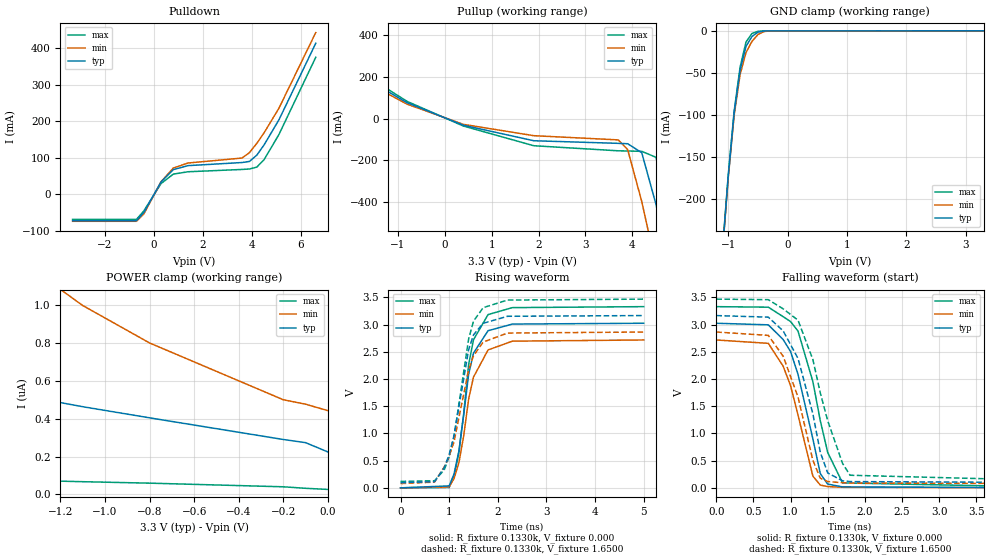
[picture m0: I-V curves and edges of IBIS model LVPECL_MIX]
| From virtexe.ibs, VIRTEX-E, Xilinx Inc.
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|   Model LVPECL_MIX
[Model]   LVPECL_MIX
Model_type   I/O
Polarity   Non-Inverting
Enable   Active-Low
Vinh  = 1.49V
Vinl  = 0.86V
Vmeas =   1.6500V
Cref =  10.0000pF
Rref =   1.0000M
Vref =  0.000V
C_comp   5.0000pF   4.0000pF   6.0000pF
[Temperature Range]   85.0000   85.0000   85.0000
[Voltage Range]   3.3000V   3.0000V   3.6000V
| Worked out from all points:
|   slope of the pulldown table from 0 to 0.495 V, typ, clamps not added: 9.94 ohm
|   slope of the pullup table from 0 to 0.495 V, typ, clamps not added: 12.6 ohm
|   GND clamp passes 1 mA (typ) near -0.45 V on its own axis
|   rising waveform, R_fixture 0.1330k, V_fixture 0.000: 20-80 % time 302ps typ, 352ps min, 285ps max; typ from 0 V to 3.02 V
|   rising waveform, R_fixture 0.1330k, V_fixture 1.6500: 20-80 % time 378ps typ, 434ps min, 360ps max; typ from 0.096 V to 3.16 V
|   falling waveform, R_fixture 0.1330k, V_fixture 0.000: 20-80 % time 326ps typ, 316ps min, 341ps max; typ from 3.02 V to 0 V
|   falling waveform, R_fixture 0.1330k, V_fixture 1.6500: 20-80 % time 345ps typ, 340ps min, 419ps max; typ from 3.16 V to 0.096 V
[Pulldown]
| voltage   I(typ)   I(min)   I(max)
-3.3V     -72.38mA   -74.24mA   -68.88mA
-700mV    -72.38mA   -74.24mA   -68.88mA
-400mV    -50.35mA   -54.31mA   -45.82mA
300mV     33.38mA    34mA       28.98mA
800mV     67.26mA    71.6mA     54.94mA
1.4V      78.19mA    85.32mA    61.41mA
3.6V      86.67mA    98.96mA    67.72mA
3.9V      89.65mA    113.9mA    68.97mA
4.2V      106.9mA    139.2mA    74.11mA
4.5V      135.4mA    168.5mA    94.89mA
5.1V      203.5mA    235.3mA    163.3mA
6.6V      413.2mA    442.5mA    374.8mA
[Pullup]
| voltage   I(typ)   I(min)   I(max)
-3.3V     404.8mA    370.8mA    438.4mA
-800mV    75.94mA    69.07mA    82.51mA
400mV     -32.24mA   -28.07mA   -36.21mA
1.9V      -106.9mA   -82.55mA   -130.9mA
3.7V      -119.4mA   -102.8mA   -155.3mA
3.9V      -121.3mA   -149.6mA   -156.2mA
4.2V      -164.4mA   -399.4mA   -157.9mA
4.5V      -410.3mA   -706.6mA   -186.2mA
4.7V      -612.9mA   -918.1mA   -329.2mA
4.9V      -822.4mA   -1.132A    -523.6mA
5.1V      -1.035A    -1.347A    -729.9mA
6.6V      -2.667A    -2.986A    -2.351A
[GND_clamp]
| voltage   I(typ)   I(min)   I(max)
-3.3V     -2.624A    -2.624A    -2.624A
-1.1V     -265.9mA   -267.2mA   -264.8mA
-1V       -174.1mA   -176mA     -172.7mA
-900mV    -98.16mA   -101.1mA   -96.02mA
-800mV    -47.1mA    -52.22mA   -43.45mA
-700mV    -18.56mA   -25.86mA   -13.29mA
-600mV    -6.79mA    -12.65mA   -3.223mA
-500mV    -1.656mA   -4.488mA   -548.6uA
-400mV    -239.4uA   -899.1uA   -68.47uA
-300mV    -25.58uA   -114.5uA   -6.532uA
3.3V      71.77nA    1.445uA    12.46nA
[POWER_clamp]
| voltage   I(typ)   I(min)   I(max)
-3.3V     1.385uA    7.507uA    174.7nA
-3.1V     1.234uA    6.162uA    158.6nA
-2.6V     941.1nA    3.772uA    125.8nA
-2.3V     808.2nA    2.826uA    110.5nA
-1.9V     666.3nA    1.95uA     93.13nA
-1.4V     530.2nA    1.266uA    75.61nA
-1.3V     506.9nA    1.168uA    72.64nA
-1.1V     463.3nA    998.2nA    66.94nA
-800mV    404.5nA    800.2nA    59.2nA
-200mV    290nA      500nA      40nA
-100mV    273.2nA    476.7nA    32nA
0V        224.2nA    442.3nA    26.08nA
[Ramp]
| variable   typ   min   max
dV/dt_r   1.8138/0.3199n   1.6296/0.3523n   1.9968/0.3075n
dV/dt_f   1.8599/0.4017n   1.7029/0.3574n   2.0076/0.5037n
R_load = 0.1330k
[Rising Waveform]
R_fixture = 0.1330k
V_fixture = 0.000
| time   V(typ)   V(min)   V(max)
0s        1.651uV    0V         2.118uV
1ns       36.04mV    17.86mV    6.385mV
1.1ns     253.3mV    168.9mV    213.4mV
1.2ns     673.5mV    460mV      648.9mV
1.3ns     1.345V     961.7mV    1.374V
1.4ns     2.081V     1.627V     2.26V
1.5ns     2.474V     2.033V     2.719V
1.8ns     2.886V     2.533V     3.182V
2.3ns     3.008V     2.694V     3.31V
5ns       3.023V     2.716V     3.328V
[Rising Waveform]
R_fixture = 0.1330k
V_fixture = 1.6500
V_fixture_min = 1.5000
V_fixture_max = 1.8000
| time   V(typ)   V(min)   V(max)
0s        95.65mV    78.43mV    118.5mV
700ps     113.8mV    105.8mV    130.8mV
900ps     370.7mV    385.2mV    332.1mV
1ns       609.6mV    580.1mV    569.6mV
1.1ns     961.6mV    846.4mV    937.7mV
1.4ns     2.534V     2.165V     2.732V
1.5ns     2.808V     2.424V     3.061V
1.7ns     3.022V     2.678V     3.309V
2.2ns     3.151V     2.843V     3.449V
5ns       3.164V     2.862V     3.466V
[Falling Waveform]
R_fixture = 0.1330k
V_fixture = 0.000
| time   V(typ)   V(min)   V(max)
0s        3.023V     2.716V     3.328V
700ps     2.994V     2.654V     3.318V
900ps     2.724V     2.235V     3.144V
1ns       2.503V     1.876V     3.054V
1.1ns     2.086V     1.336V     2.879V
1.3ns     900mV      216mV      1.951V
1.4ns     262.3mV    51.08mV    1.233V
1.5ns     69.3mV     23.51mV    648.5mV
1.7ns     17.74mV    10.91mV    91mV
5ns       197.8uV    217.1uV    265.1uV
[Falling Waveform]
R_fixture = 0.1330k
V_fixture = 1.6500
V_fixture_min = 1.5000
V_fixture_max = 1.8000
| time   V(typ)   V(min)   V(max)
0s        3.164V     2.862V     3.466V
700ps     3.135V     2.8V       3.456V
900ps     2.883V     2.418V     3.288V
1.1ns     2.377V     1.668V     3.079V
1.3ns     1.361V     506.1mV    2.357V
1.4ns     653.3mV    176.6mV    1.744V
1.5ns     273mV      116.2mV    1.232V
1.7ns     130.2mV    93.94mV    448.4mV
1.8ns     115.3mV    89.17mV    231.9mV
5ns       95.86mV    78.71mV    118.7mV
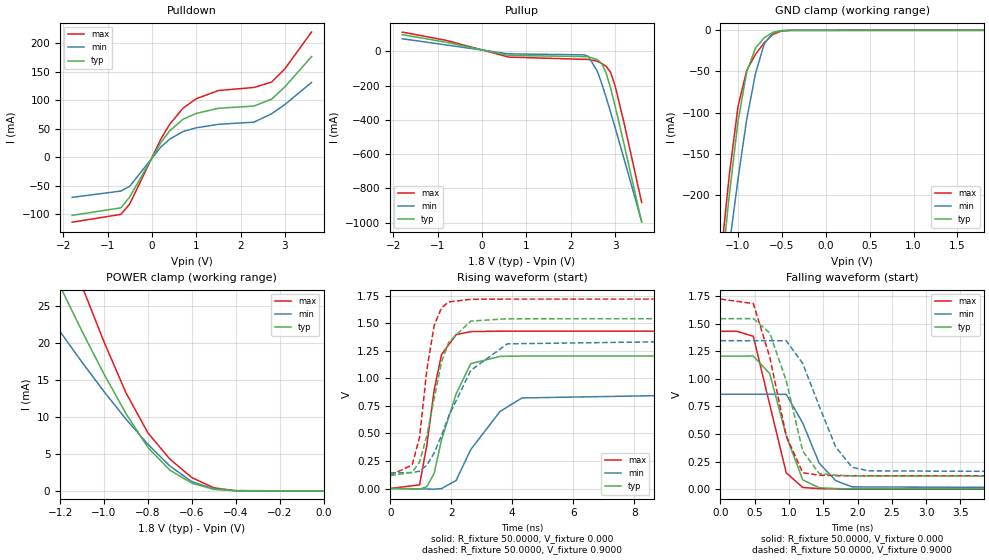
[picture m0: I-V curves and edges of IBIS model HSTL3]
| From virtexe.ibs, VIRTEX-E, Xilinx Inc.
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|   Model HSTL3
[Model]   HSTL3
Model_type   I/O
Polarity   Non-Inverting
Enable   Active-Low
Vmeas =   0.9000V
Vinl =  0.8000V
Vinh =  1.0000V
Cref =  20.0000pF
Rref =  50.0000
Vref =   0.9000V
C_comp   6.0000pF   5.0000pF   7.0000pF
[Temperature Range]   25.0000   100.0000   0.000
[Voltage Range]   1.8000V   1.7000V   1.9000V
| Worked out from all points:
|   slope of the pulldown table from 0 to 0.27 V, typ, clamps not added: 8.08 ohm
|   slope of the pullup table from 0 to 0.27 V, typ, clamps not added: 20.1 ohm
|   GND clamp passes 1 mA (typ) near -0.54 V on its own axis
|   POWER clamp passes 1 mA (typ) near -0.59 V on its own axis
|   rising waveform, R_fixture 50.0000, V_fixture 0.000: 20-80 % time 777ps typ, 1.23ns min, 498ps max; typ from 0 V to 1.21 V
|   rising waveform, R_fixture 50.0000, V_fixture 0.9000: 20-80 % time 702ps typ, 1.21ns min, 457ps max; typ from 0.116 V to 1.54 V
|   falling waveform, R_fixture 50.0000, V_fixture 0.000: 20-80 % time 351ps typ, 419ps min, 333ps max; typ from 1.21 V to 0 V
|   falling waveform, R_fixture 50.0000, V_fixture 0.9000: 20-80 % time 372ps typ, 459ps min, 372ps max; typ from 1.54 V to 0.116 V
[Pulldown]
| voltage   I(typ)   I(min)   I(max)
-1.8V     -101.8mA   -70.26mA   -113.8mA
-700mV    -88.66mA   -59.16mA   -100.1mA
-500mV    -69.51mA   -50.85mA   -81.74mA
200mV     25.8mA     17.93mA    31.7mA
400mV     46.21mA    31.81mA    57.78mA
700mV     66.68mA    45.16mA    86.08mA
1V        76.94mA    51.73mA    102.7mA
1.5V      85.98mA    57.82mA    117.1mA
2.3V      89.85mA    61.65mA    122.5mA
2.7V      102mA      76.37mA    131.9mA
3V        123.6mA    92.61mA    155.3mA
3.6V      176.6mA    131.3mA    219.6mA
[Pullup]
| voltage   I(typ)   I(min)   I(max)
-1.8V     97.04mA    72.78mA    111.7mA
-800mV    51.88mA    36.3mA     62.98mA
600mV     -24.24mA   -15.32mA   -34.04mA
2.3V      -31.3mA    -20.95mA   -47.36mA
2.4V      -32.73mA   -30.87mA   -47.8mA
2.6V      -49.01mA   -116.6mA   -58.63mA
2.7V      -71.91mA   -188.9mA   -71.8mA
2.8V      -127.2mA   -270.6mA   -88.68mA
2.9V      -216mA     -356.6mA   -122.6mA
3V        -319mA     -444.8mA   -201.1mA
3.2V      -539.1mA   -625.1mA   -414.5mA
3.6V      -997.5mA   -993.6mA   -882.6mA
[GND_clamp]
| voltage   I(typ)   I(min)   I(max)
-1.8V     -984.2mA   -893.8mA   -981.3mA
-1.2V     -305.4mA   -349.4mA   -281.7mA
-1.1V     -201.6mA   -263.3mA   -177.2mA
-1V       -111.1mA   -181.2mA   -92.91mA
-900mV    -50.62mA   -108.2mA   -48.68mA
-800mV    -21.39mA   -52.51mA   -29.19mA
-700mV    -9.057mA   -16.26mA   -15mA
-600mV    -2.332mA   -3.044mA   -4.887mA
-500mV    -280.5uA   -493uA     -684.1uA
-400mV    -21.31uA   -72.94uA   -46.93uA
1.8V      9.75nA     24.68nA    9.371nA
[POWER_clamp]
| voltage   I(typ)   I(min)   I(max)
-1.8V     67.36mA    47.92mA    87.19mA
-1.3V     33.96mA    25.81mA    43.76mA
-1.2V     27.64mA    21.52mA    35.56mA
-1.1V     21.56mA    17.38mA    27.65mA
-1V       15.79mA    13.42mA    20.13mA
-900mV    10.45mA    9.702mA    13.26mA
-800mV    5.872mA    6.297mA    7.84mA
-700mV    2.804mA    3.371mA    4.298mA
-600mV    1.052mA    1.252mA    1.806mA
-500mV    210uA      278.7uA    420.1uA
-400mV    17.08uA    35.57uA    36.55uA
0V        9.75nA     16.07nA    10.24nA
[Ramp]
| variable   typ   min   max
dV/dt_r   0.7230/0.7358n   0.5157/1.2099n   0.8580/0.4715n
dV/dt_f   0.9319/0.3893n   0.8220/0.5882n   1.0115/0.3214n
R_load = 50.0000
[Rising Waveform]
R_fixture = 50.0000
V_fixture = 0.000
| time   V(typ)   V(min)   V(max)
0s        -41.76uV   -22.54uV   -60.93uV
960ps     -5.628mV   -2.364mV   33.39mV
1.2ns     16.2mV     -4.894mV   394.4mV
1.44ns    137.6mV    -6.008mV   894.9mV
1.68ns    441.5mV    -772.3uV   1.217V
2.16ns    859.5mV    73.07mV    1.399V
2.64ns    1.135V     354mV      1.426V
3.6ns     1.201V     700.1mV    1.43V
4.32ns    1.204V     823.2mV    1.43V
12ns      1.205V     859.5mV    1.43V
[Rising Waveform]
R_fixture = 50.0000
V_fixture = 0.9000
V_fixture_min = 0.8000
V_fixture_max = 1.1000
| time   V(typ)   V(min)   V(max)
0s        116.4mV    142.1mV    119.4mV
720ps     147.5mV    143.8mV    214.8mV
960ps     239.5mV    157.8mV    466.6mV
1.2ns     480.3mV    213.7mV    1.078V
1.44ns    818.7mV    322.8mV    1.482V
1.68ns    1.15V      481.4mV    1.642V
1.92ns    1.331V     658.7mV    1.696V
2.64ns    1.522V     1.073V     1.72V
3.84ns    1.543V     1.315V     1.722V
12ns      1.544V     1.345V     1.722V
[Falling Waveform]
R_fixture = 50.0000
V_fixture = 0.000
| time   V(typ)   V(min)   V(max)
0s        1.205V     859.6mV    1.43V
240ps     1.205V     859.6mV    1.43V
480ps     1.206V     859.6mV    1.385V
720ps     1.046V     859.9mV    764.1mV
960ps     482.6mV    858.9mV    148mV
1.2ns     84.3mV     599.6mV    15.72mV
1.44ns    13.28mV    236.2mV    4.709mV
1.68ns    5.358mV    77.77mV    2.238mV
1.92ns    2.688mV    20.56mV    1.234mV
12ns      55.62uV    99.74uV    40.95uV
[Falling Waveform]
R_fixture = 50.0000
V_fixture = 0.9000
V_fixture_min = 0.8000
V_fixture_max = 1.1000
| time   V(typ)   V(min)   V(max)
0s        1.544V     1.345V     1.722V
480ps     1.545V     1.345V     1.681V
720ps     1.415V     1.345V     1.197V
960ps     982.1mV    1.345V     482.6mV
1.2ns     345mV      1.139V     149.3mV
1.44ns    142.4mV    754mV      127mV
1.68ns    125.8mV    383.2mV    122.8mV
1.92ns    120.8mV    198.5mV    121.2mV
2.16ns    119mV      165.9mV    120.6mV
12ns      116.5mV    142.2mV    119.6mV
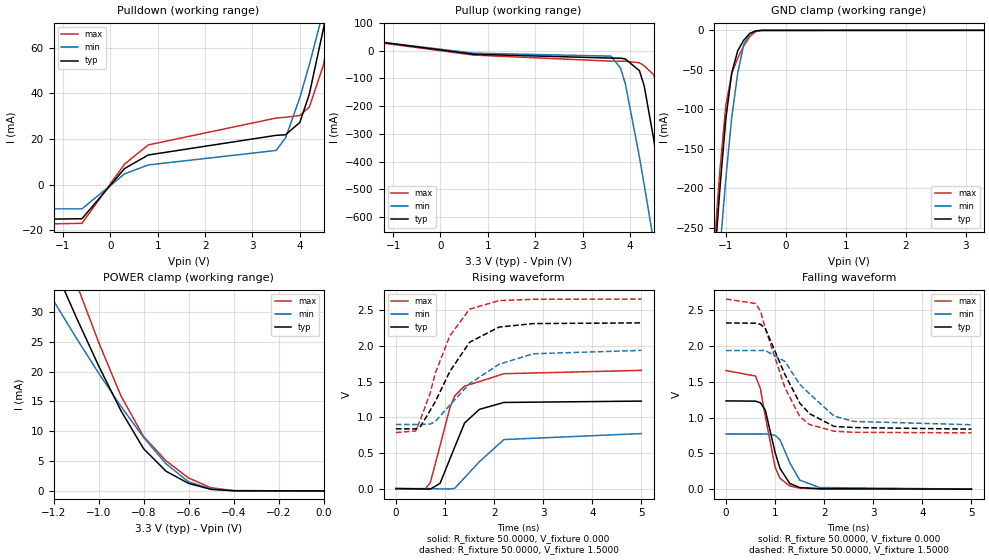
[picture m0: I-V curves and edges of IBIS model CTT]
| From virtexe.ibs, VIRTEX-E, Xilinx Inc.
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|   Model CTT
[Model]   CTT
Model_type   I/O
Polarity   Non-Inverting
Enable   Active-Low
Vinl =   1.300V
Vinh =   1.700V
Vmeas =   1.5000V
Cref =  20.0000pF
Rref =  50.0000
Vref =   1.5000V
C_comp   5.0000pF   4.0000pF   6.0000pF
[Temperature Range]   25.0000   100.0000   0.000
[Voltage Range]   3.3000V   3.0000V   3.6000V
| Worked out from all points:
|   slope of the pulldown table from 0 to 0.495 V, typ, clamps not added: 48.8 ohm
|   slope of the pullup table from 0 to 0.495 V, typ, clamps not added: 53.2 ohm
|   GND clamp passes 1 mA (typ) near -0.51 V on its own axis
|   POWER clamp passes 1 mA (typ) near -0.57 V on its own axis
|   rising waveform, R_fixture 50.0000, V_fixture 0.000: 20-80 % time 463ps typ, 641ps min, 427ps max; typ from 0 V to 1.23 V
|   rising waveform, R_fixture 50.0000, V_fixture 1.5000: 20-80 % time 737ps typ, 1.07ns min, 612ps max; typ from 0.838 V to 2.32 V
|   falling waveform, R_fixture 50.0000, V_fixture 0.000: 20-80 % time 288ps typ, 318ps min, 271ps max; typ from 1.23 V to 0.001 V
|   falling waveform, R_fixture 50.0000, V_fixture 1.5000: 20-80 % time 668ps typ, 798ps min, 589ps max; typ from 2.32 V to 0.839 V
[Pulldown]
| voltage   I(typ)   I(min)   I(max)
-3.3V     -15.5mA    -10.58mA   -17.86mA
-600mV    -14.92mA   -10.58mA   -16.93mA
300mV     7.091mA    4.772mA    9.036mA
800mV     13.02mA    8.645mA    17.43mA
3.5V      21.63mA    15.01mA    29.2mA
3.7V      21.89mA    20.56mA    29.55mA
4V        27.27mA    38.14mA    30.32mA
4.2V      39.63mA    52.54mA    34mA
4.5V      68.49mA    76.43mA    52.45mA
4.7V      90.09mA    93.42mA    75.12mA
4.9V      112.8mA    111.1mA    100.8mA
6.6V      325.4mA    277.2mA    349.4mA
[Pullup]
| voltage   I(typ)   I(min)   I(max)
-3.3V     76.5mA     72.6mA     74.8mA
700mV     -12.61mA   -8.706mA   -15.61mA
3.6V      -26.42mA   -19.4mA    -37.49mA
3.8V      -26.91mA   -62.44mA   -37.69mA
3.9V      -29.44mA   -116.9mA   -37.79mA
4.2V      -71.79mA   -383mA     -43.41mA
4.3V      -126.2mA   -482.7mA   -54.06mA
4.5V      -317.3mA   -687.1mA   -86.33mA
4.7V      -537mA     -895.1mA   -197.6mA
4.9V      -764.2mA   -1.105A    -410.4mA
5.1V      -994.9mA   -1.316A    -641.1mA
6.6V      -2.76A     -2.923A    -2.453A
[GND_clamp]
| voltage   I(typ)   I(min)   I(max)
-3.3V     -2.749A    -2.594A    -2.804A
-1.2V     -306mA     -377.1mA   -282.7mA
-1.1V     -202.5mA   -280mA     -178.8mA
-1V       -112.5mA   -188.5mA   -95.98mA
-900mV    -53.5mA    -109.7mA   -54.53mA
-800mV    -25.67mA   -53.59mA   -35.13mA
-700mV    -12.44mA   -17.88mA   -19.82mA
-600mV    -3.982mA   -4.202mA   -7.865mA
-500mV    -601.5uA   -800.3uA   -1.508mA
-400mV    -51.05uA   -119.3uA   -124.3uA
3.3V      18.74nA    3.634uA    18.92nA
[POWER_clamp]
| voltage   I(typ)   I(min)   I(max)
-3.3V     237mA      175.9mA    284.4mA
-1.3V     46.69mA    38.29mA    56.33mA
-1.2V     37.79mA    31.9mA     45.45mA
-1.1V     29.2mA     25.71mA    34.95mA
-1V       21.01mA    19.78mA    24.97mA
-900mV    13.43mA    14.17mA    15.91mA
-800mV    7.091mA    8.993mA    9.139mA
-700mV    3.305mA    4.554mA    5.052mA
-600mV    1.265mA    1.529mA    2.172mA
-500mV    263.8uA    333.6uA    531.5uA
-400mV    22.63uA    44.12uA    49.77uA
0V        18.8nA     38.3nA     22.53nA
[Ramp]
| variable   typ   min   max
dV/dt_r   0.7362/0.4850n   0.4628/0.6207n   0.9948/0.4203n
dV/dt_f   0.5880/0.9072n   0.3906/1.1424n   0.7668/0.7460n
R_load = 50.0000
[Rising Waveform]
R_fixture = 50.0000
V_fixture = 0.000
| time   V(typ)   V(min)   V(max)
0s        3.924uV    4.384uV    3.833uV
600ps     -5.891mV   173.9uV    -3.731mV
700ps     -8.182mV   -336.5uV   81.63mV
900ps     73.9mV     -4.578mV   603.2mV
1.1ns     416.1mV    -5.173mV   1.135V
1.2ns     585.5mV    4.49mV     1.302V
1.4ns     920.9mV    153.5mV    1.438V
1.7ns     1.111V     376.5mV    1.5V
2.2ns     1.208V     687.5mV    1.611V
5ns       1.227V     771.4mV    1.658V
[Rising Waveform]
R_fixture = 50.0000
V_fixture = 1.5000
V_fixture_min = 1.3500
V_fixture_max = 1.6500
| time   V(typ)   V(min)   V(max)
0s        837.7mV    898.6mV    786mV
400ps     837.3mV    898.7mV    808.4mV
500ps     869.7mV    898.6mV    967.7mV
700ps     1.099V     905.4mV    1.344V
800ps     1.216V     939.8mV    1.615V
1.1ns     1.645V     1.173V     2.144V
1.5ns     2.052V     1.471V     2.516V
2.1ns     2.265V     1.744V     2.636V
2.8ns     2.314V     1.891V     2.655V
5ns       2.324V     1.938V     2.658V
[Falling Waveform]
R_fixture = 50.0000
V_fixture = 0.000
| time   V(typ)   V(min)   V(max)
0s        1.234V     771.5mV    1.658V
600ps     1.231V     771.5mV    1.582V
700ps     1.208V     771.6mV    1.405V
800ps     1.105V     772mV      1.017V
1ns       511.8mV    753mV      306.5mV
1.1ns     288.8mV    690.7mV    151.8mV
1.3ns     78.72mV    367.5mV    44.82mV
1.5ns     23.12mV    127.9mV    15.44mV
1.9ns     6.899mV    23.32mV    5.324mV
5ns       503.8uV    249.8uV    435.9uV
[Falling Waveform]
R_fixture = 50.0000
V_fixture = 1.5000
V_fixture_min = 1.3500
V_fixture_max = 1.6500
| time   V(typ)   V(min)   V(max)
0s        2.324V     1.938V     2.658V
600ps     2.321V     1.938V     2.596V
700ps     2.305V     1.938V     2.493V
800ps     2.246V     1.939V     2.249V
1.2ns     1.603V     1.786V     1.419V
1.5ns     1.206V     1.467V     1.018V
1.7ns     1.056V     1.333V     904.1mV
2.2ns     877.9mV    1.022V     810.8mV
2.6ns     861.6mV    947.4mV    795.2mV
5ns       839.2mV    901.1mV    787.1mV
